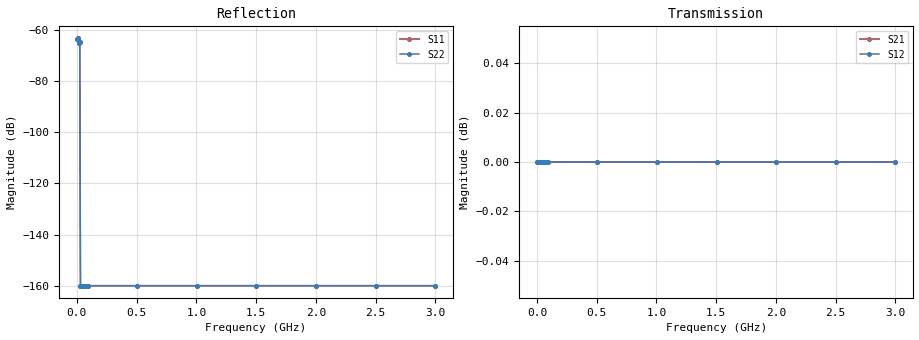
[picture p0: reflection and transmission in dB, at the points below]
! ListType=Lin
!!HP85032B thru 0.1 to 3000MHz 500 points
# MHZ S RI R 50
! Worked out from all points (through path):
!   500 points, 100 kHz to 3 GHz, reference 50 ohm
!   highest |S21| = 0.00 dB at 100 kHz (marker M1); lowest = 0.0 dB at 100 kHz (marker M2)
!   lowest |S11| = -65.2 dB at 18.14 MHz (marker M3), VSWR 1.00, Z = 50 - j0.0241 ohm
!   |S11| at or under -10 dB: start of sweep to end of sweep
!   |S22| runs from - to -63.3 dB; largest |S21 - S12| = 0
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0.1  -0.000593 -0.000306  1 0  1 0  -0.000593 -0.000306
6.111824  -0.000604 -0.000312  1 0  1 0  -0.000604 -0.000312
12.12365  -0.000602 -0.000264  1 0  1 0  -0.000602 -0.000264
18.13547  -0.000491 -0.000242  1 0  1 0  -0.000491 -0.000242
24.14729  -0.00052 -0.000242  1 0  1 0  -0.00052 -0.000242
30.15912  0 0  1 0  1 0  0 0
36.17094  0 0  1 0  1 0  0 0
42.18277  0 0  1 0  1 0  0 0
48.19459  0 0  1 0  1 0  0 0
54.20641  0 0  1 0  1 0  0 0
60.21824  0 0  1 0  1 0  0 0
66.23006  0 0  1 0  1 0  0 0
72.24188  0 0  1 0  1 0  0 0
78.25371  0 0  1 0  1 0  0 0
84.26553  0 0  1 0  1 0  0 0
90.27735  0 0  1 0  1 0  0 0
505.0932  0 0  1 0  1 0  0 0
1004.075  0 0  1 0  1 0  0 0
1503.056  0 0  1 0  1 0  0 0
2002.037  0 0  1 0  1 0  0 0
2501.019  0 0  1 0  1 0  0 0
3000  0 0  1 0  1 0  0 0
